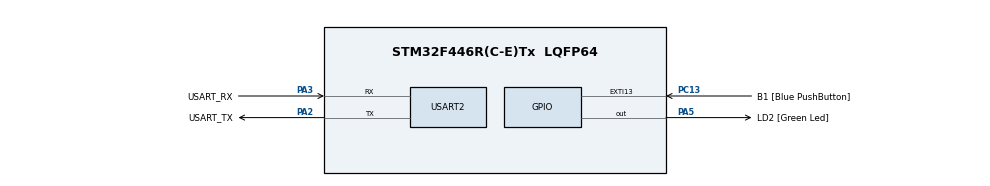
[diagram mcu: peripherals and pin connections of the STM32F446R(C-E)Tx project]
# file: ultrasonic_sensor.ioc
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Mcu.Family=STM32F4
Mcu.Name=STM32F446R(C-E)Tx
Mcu.Package=LQFP64
NVIC.PriorityGroup=NVIC_PRIORITYGROUP_0
PA13.GPIO_Label=TMS
PA13.Mode=Serial_Wire
PA13.Signal=SYS_JTMS-SWDIO
PA14.GPIO_Label=TCK
PA14.Mode=Serial_Wire
PA14.Signal=SYS_JTCK-SWCLK
PA2.GPIO_Label=USART_TX
PA2.Mode=Asynchronous
PA2.Signal=USART2_TX
PA3.GPIO_Label=USART_RX
PA3.Mode=Asynchronous
PA3.Signal=USART2_RX
PA5.GPIO_Label=LD2 [Green Led]
PA5.Signal=GPIO_Output
PB3.GPIO_Label=SWO
PB3.Signal=SYS_JTDO-SWO
PC13.GPIO_Label=B1 [Blue PushButton]
PC13.GPIO_ModeDefaultEXTI=GPIO_MODE_IT_FALLING
PC13.Signal=GPXTI13
PC14-OSC32_IN.Mode=LSE-External-Oscillator
PC14-OSC32_IN.Signal=RCC_OSC32_IN
PC15-OSC32_OUT.Mode=LSE-External-Oscillator
PC15-OSC32_OUT.Signal=RCC_OSC32_OUT
PH0-OSC_IN.Mode=HSE-External-Oscillator
PH0-OSC_IN.Signal=RCC_OSC_IN
PH1-OSC_OUT.Mode=HSE-External-Oscillator
PH1-OSC_OUT.Signal=RCC_OSC_OUT
ProjectManager.HeapSize=0x200
ProjectManager.StackSize=0x400
ProjectManager.TargetToolchain=STM32CubeIDE
RCC.48MHZClocksFreq_Value=84000000
RCC.AHBFreq_Value=100000000
RCC.APB1CLKDivider=RCC_HCLK_DIV4
RCC.APB1Freq_Value=25000000
RCC.APB1TimFreq_Value=50000000
RCC.APB2CLKDivider=RCC_HCLK_DIV2
RCC.APB2Freq_Value=50000000
RCC.APB2TimFreq_Value=100000000
RCC.CortexFreq_Value=100000000
RCC.FLatency-AdvancedSettings=FLASH_LATENCY_3
RCC.HCLKFreq_Value=100000000
RCC.HSE_VALUE=8000000
RCC.HSI_VALUE=16000000
RCC.PLLM=8
RCC.PLLN=100
RCC.SYSCLKFreq_VALUE=100000000
RCC.SYSCLKSource=RCC_SYSCLKSOURCE_PLLCLK
RCC.USBFreq_Value=100000000
RCC.VCOOutputFreq_Value=200000000
TIM1.Period=0xffff-1
TIM1.Prescaler=100-1
USART2.VirtualMode=VM_ASYNC
VP_TIM1_VS_ClockSourceINT.Mode=Internal
board=NUCLEO-F446RE

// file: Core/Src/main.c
#include "main.h"

TIM_HandleTypeDef htim1;
UART_HandleTypeDef huart2;

uint32_t echo_time, sensor_time;
float distance;
char uart_data_buff[10]; //Fixed Size!

void SystemClock_Config(void);
static void MX_GPIO_Init(void);
static void MX_USART2_UART_Init(void);
static void MX_TIM1_Init(void);

void delay_us(uint32_t us){
	__HAL_TIM_SET_COUNTER(&htim1, 0);
	while ((__HAL_TIM_GET_COUNTER(&htim1)) < us);
}

uint32_t HCSR04_read (void){
	echo_time = 0;

	// Pull TRIG pin low for at least 2 us
	HAL_GPIO_WritePin(GPIOA, GPIO_PIN_1, GPIO_PIN_RESET);
	delay_us(2);

	// Keep TRIG pin High for 10 us for start the sensor
	HAL_GPIO_WritePin(GPIOA, GPIO_PIN_1, GPIO_PIN_SET);
	delay_us(10);
	HAL_GPIO_WritePin(GPIOA, GPIO_PIN_1, GPIO_PIN_RESET);

	// Wait for the ECHO pin to go high
	while (!(HAL_GPIO_ReadPin(GPIOA, GPIO_PIN_4)));
	// Measure time for which the pin is high
	while (HAL_GPIO_ReadPin(GPIOA, GPIO_PIN_4)){
		echo_time++;
		delay_us(1);
	}
	// The delay of 1us give 1.8us (measured by scope)
	return echo_time*1.8;
}

int main(void){
	/* MCU Configuration--------------------------------------------------------*/
	/* Reset of all peripherals, Initializes the Flash interface and the Systick. */
	HAL_Init();
	/* Configure the system clock */
	SystemClock_Config();
	/* Initialize all configured peripherals */
	MX_GPIO_Init();
	MX_USART2_UART_Init();
	MX_TIM1_Init();
	/* Start Timer 1*/
	HAL_TIM_Base_Start(&htim1);

	/* Infinite loop */
	while (1){
		// Read from sensor
		sensor_time = HCSR04_read();
		// d = (t * 0.0343)/2
		distance  = sensor_time * (0.0343)/2;
		// LED toggle
		HAL_GPIO_TogglePin(GPIOA, GPIO_PIN_5);
		// UART TX
		sprintf(uart_data_buff, "\r%.5f\n", distance);
		HAL_UART_Transmit(&huart2, (uint8_t *)uart_data_buff, sizeof(uart_data_buff), HAL_MAX_DELAY);
		// Delay (at least 60ms before new read)
		HAL_Delay(100);
	}
}

void SystemClock_Config(void)
{
  RCC_OscInitTypeDef RCC_OscInitStruct = {0};
  RCC_ClkInitTypeDef RCC_ClkInitStruct = {0};

  /** Configure the main internal regulator output voltage
  */
  __HAL_RCC_PWR_CLK_ENABLE();
  __HAL_PWR_VOLTAGESCALING_CONFIG(PWR_REGULATOR_VOLTAGE_SCALE3);
  /** Initializes the CPU, AHB and APB busses clocks
  */
  RCC_OscInitStruct.OscillatorType = RCC_OSCILLATORTYPE_HSI;
  RCC_OscInitStruct.HSIState = RCC_HSI_ON;
  RCC_OscInitStruct.HSICalibrationValue = RCC_HSICALIBRATION_DEFAULT;
  RCC_OscInitStruct.PLL.PLLState = RCC_PLL_ON;
  RCC_OscInitStruct.PLL.PLLSource = RCC_PLLSOURCE_HSI;
  RCC_OscInitStruct.PLL.PLLM = 16;
  RCC_OscInitStruct.PLL.PLLN = 336;
  RCC_OscInitStruct.PLL.PLLP = RCC_PLLP_DIV4;
  RCC_OscInitStruct.PLL.PLLQ = 2;
  RCC_OscInitStruct.PLL.PLLR = 2;
  if (HAL_RCC_OscConfig(&RCC_OscInitStruct) != HAL_OK)
  {
    Error_Handler();
  }
  /** Initializes the CPU, AHB and APB busses clocks
  */
  RCC_ClkInitStruct.ClockType = RCC_CLOCKTYPE_HCLK|RCC_CLOCKTYPE_SYSCLK
                              |RCC_CLOCKTYPE_PCLK1|RCC_CLOCKTYPE_PCLK2;
  RCC_ClkInitStruct.SYSCLKSource = RCC_SYSCLKSOURCE_PLLCLK;
  RCC_ClkInitStruct.AHBCLKDivider = RCC_SYSCLK_DIV1;
  RCC_ClkInitStruct.APB1CLKDivider = RCC_HCLK_DIV2;
  RCC_ClkInitStruct.APB2CLKDivider = RCC_HCLK_DIV1;

  if (HAL_RCC_ClockConfig(&RCC_ClkInitStruct, FLASH_LATENCY_2) != HAL_OK)
  {
    Error_Handler();
  }
}

static void MX_TIM1_Init(void){

  TIM_ClockConfigTypeDef sClockSourceConfig = {0};
  TIM_MasterConfigTypeDef sMasterConfig = {0};

  htim1.Instance = TIM1;
  htim1.Init.Prescaler = 84-1;
  htim1.Init.CounterMode = TIM_COUNTERMODE_UP;
  htim1.Init.Period = 0xfff-1;
  htim1.Init.ClockDivision = TIM_CLOCKDIVISION_DIV1;
  htim1.Init.RepetitionCounter = 0;
  htim1.Init.AutoReloadPreload = TIM_AUTORELOAD_PRELOAD_DISABLE;
  HAL_TIM_Base_Init(&htim1);

  sClockSourceConfig.ClockSource = TIM_CLOCKSOURCE_INTERNAL;
  HAL_TIM_ConfigClockSource(&htim1, &sClockSourceConfig);

  sMasterConfig.MasterOutputTrigger = TIM_TRGO_RESET;
  sMasterConfig.MasterSlaveMode = TIM_MASTERSLAVEMODE_DISABLE;
  HAL_TIMEx_MasterConfigSynchronization(&htim1, &sMasterConfig);

}

static void MX_USART2_UART_Init(void)
{

  huart2.Instance = USART2;
  huart2.Init.BaudRate = 115200;
  huart2.Init.WordLength = UART_WORDLENGTH_8B;
  huart2.Init.StopBits = UART_STOPBITS_1;
  huart2.Init.Parity = UART_PARITY_NONE;
  huart2.Init.Mode = UART_MODE_TX_RX;
  huart2.Init.HwFlowCtl = UART_HWCONTROL_NONE;
  huart2.Init.OverSampling = UART_OVERSAMPLING_16;
  if (HAL_UART_Init(&huart2) != HAL_OK)
  {
    Error_Handler();
  }

}

static void MX_GPIO_Init(void)
{
  GPIO_InitTypeDef GPIO_InitStruct = {0};

  /* GPIO Ports Clock Enable */
  __HAL_RCC_GPIOC_CLK_ENABLE();
  __HAL_RCC_GPIOH_CLK_ENABLE();
  __HAL_RCC_GPIOA_CLK_ENABLE();
  __HAL_RCC_GPIOB_CLK_ENABLE();

  /*Configure GPIO pin Output Level */
  HAL_GPIO_WritePin(LD2_GPIO_Port, LD2_Pin, GPIO_PIN_RESET);

  /*Configure GPIO pin : B1_Pin */
  GPIO_InitStruct.Pin = B1_Pin;
  GPIO_InitStruct.Mode = GPIO_MODE_IT_FALLING;
  GPIO_InitStruct.Pull = GPIO_NOPULL;
  HAL_GPIO_Init(B1_GPIO_Port, &GPIO_InitStruct);

  /*Configure GPIO pin : LD2_Pin */
  GPIO_InitStruct.Pin = LD2_Pin;
  GPIO_InitStruct.Mode = GPIO_MODE_OUTPUT_PP;
  GPIO_InitStruct.Pull = GPIO_NOPULL;
  GPIO_InitStruct.Speed = GPIO_SPEED_FREQ_LOW;
  HAL_GPIO_Init(LD2_GPIO_Port, &GPIO_InitStruct);

  /*Configure GPIO pin Output Level */
  HAL_GPIO_WritePin(GPIOA, GPIO_PIN_1, GPIO_PIN_RESET);

  /*Configure GPIO pin : PA1 */
  GPIO_InitStruct.Pin = GPIO_PIN_1;
  GPIO_InitStruct.Mode = GPIO_MODE_OUTPUT_PP;
  GPIO_InitStruct.Pull = GPIO_NOPULL;
  GPIO_InitStruct.Speed = GPIO_SPEED_FREQ_LOW;
  HAL_GPIO_Init(GPIOA, &GPIO_InitStruct);

  /*Configure GPIO pin : PA4 */
  GPIO_InitStruct.Pin = GPIO_PIN_4;
  GPIO_InitStruct.Mode = GPIO_MODE_INPUT;
  GPIO_InitStruct.Pull = GPIO_NOPULL;
  HAL_GPIO_Init(GPIOA, &GPIO_InitStruct);
}

void Error_Handler(void)
{
}

/************************ (C) COPYRIGHT STMicroelectronics *****END OF FILE****/
